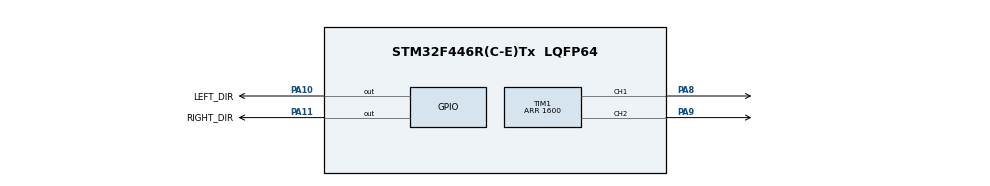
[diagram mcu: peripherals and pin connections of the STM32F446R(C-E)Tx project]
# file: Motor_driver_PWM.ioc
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Mcu.Family=STM32F4
Mcu.Name=STM32F446R(C-E)Tx
Mcu.Package=LQFP64
NVIC.PriorityGroup=NVIC_PRIORITYGROUP_4
PA10.GPIO_Label=LEFT_DIR
PA10.GPIO_Speed=GPIO_SPEED_FREQ_HIGH
PA10.Signal=GPIO_Output
PA11.GPIO_Label=RIGHT_DIR
PA11.GPIO_Speed=GPIO_SPEED_FREQ_HIGH
PA11.Signal=GPIO_Output
PA8.GPIO_Speed=GPIO_SPEED_FREQ_LOW
PA8.Signal=S_TIM1_CH1
PA9.GPIO_Speed=GPIO_SPEED_FREQ_LOW
PA9.Signal=S_TIM1_CH2
PH0-OSC_IN.Mode=HSE-External-Oscillator
PH0-OSC_IN.Signal=RCC_OSC_IN
PH1-OSC_OUT.Mode=HSE-External-Oscillator
PH1-OSC_OUT.Signal=RCC_OSC_OUT
ProjectManager.HeapSize=0x200
ProjectManager.StackSize=0x400
ProjectManager.TargetToolchain=STM32CubeIDE
RCC.AHBCLKDivider=RCC_SYSCLK_DIV2
RCC.AHBFreq_Value=32000000
RCC.APB1Freq_Value=32000000
RCC.APB1TimFreq_Value=32000000
RCC.APB2Freq_Value=32000000
RCC.APB2TimFreq_Value=32000000
RCC.CortexFreq_Value=32000000
RCC.HCLKFreq_Value=32000000
RCC.PLLM=8
RCC.PLLN=64
RCC.SYSCLKFreq_VALUE=64000000
RCC.SYSCLKSource=RCC_SYSCLKSOURCE_PLLCLK
RCC.USBFreq_Value=64000000
RCC.VCOOutputFreq_Value=128000000
SH.S_TIM1_CH1.0=TIM1_CH1,PWM Generation1 CH1
SH.S_TIM1_CH2.0=TIM1_CH2,PWM Generation2 CH2
TIM1.Channel-PWM\ Generation1\ CH1=TIM_CHANNEL_1
TIM1.Channel-PWM\ Generation2\ CH2=TIM_CHANNEL_2
TIM1.OCMode_PWM-PWM\ Generation2\ CH2=TIM_OCMODE_PWM2
TIM1.Period=1600
TIM1.Pulse-PWM\ Generation1\ CH1=800
TIM1.Pulse-PWM\ Generation2\ CH2=800
board=custom

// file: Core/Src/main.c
/* USER CODE BEGIN Header */
/**
  ******************************************************************************
  * @file           : main.c
  * @brief          : Main program body
  ******************************************************************************
  * @attention
  *
  * <h2><center>&copy; Copyright (c) 2020 STMicroelectronics.
  * All rights reserved.</center></h2>
  *
  * This software component is licensed by ST under BSD 3-Clause license,
  * the "License"; You may not use this file except in compliance with the
  * License. You may obtain a copy of the License at:
  *                        opensource.org/licenses/BSD-3-Clause
  *
  ******************************************************************************
  */
/* USER CODE END Header */
#include "main.h"

TIM_HandleTypeDef htim1;

void SystemClock_Config(void);
static void MX_GPIO_Init(void);

/* USER CODE BEGIN PFP */
void move_forward(int pulse);
void turn_left(int pulse);
void turn_right(int pulse);
void reverse(int pulse);
void stop_robot(void);
static void MX_TIM1_Init(void);

/* USER CODE END PFP */

int main(void)
{

  /* MCU Configuration--------------------------------------------------------*/

  /* Reset of all peripherals, Initializes the Flash interface and the Systick. */
  HAL_Init();

  /* Configure the system clock */
  SystemClock_Config();

  /* Initialize all configured peripherals */
  MX_GPIO_Init();
  MX_TIM1_Init();

  /* USER CODE BEGIN 2 */
  HAL_TIM_PWM_Start(&htim1, TIM_CHANNEL_1);
  HAL_TIM_PWM_Start(&htim1, TIM_CHANNEL_2);

  /* USER CODE END 2 */

  /* Infinite loop */
  while (1)
  {

  }
}

void SystemClock_Config(void)
{
  RCC_OscInitTypeDef RCC_OscInitStruct = {0};
  RCC_ClkInitTypeDef RCC_ClkInitStruct = {0};

  /** Configure the main internal regulator output voltage
  */

  __HAL_RCC_PWR_CLK_ENABLE();
  __HAL_PWR_VOLTAGESCALING_CONFIG(PWR_REGULATOR_VOLTAGE_SCALE3);

  /** Initializes the RCC Oscillators according to the specified parameters
  * in the RCC_OscInitTypeDef structure.
  */

  RCC_OscInitStruct.OscillatorType = RCC_OSCILLATORTYPE_HSI;
  RCC_OscInitStruct.HSIState = RCC_HSI_ON;
  RCC_OscInitStruct.HSICalibrationValue = RCC_HSICALIBRATION_DEFAULT;
  RCC_OscInitStruct.PLL.PLLState = RCC_PLL_NONE;

  if (HAL_RCC_OscConfig(&RCC_OscInitStruct) != HAL_OK)
  {
    Error_Handler();
  }

  /** Initializes the CPU, AHB and APB buses clocks
  */
  RCC_ClkInitStruct.ClockType = RCC_CLOCKTYPE_HCLK|RCC_CLOCKTYPE_SYSCLK
                              |RCC_CLOCKTYPE_PCLK1|RCC_CLOCKTYPE_PCLK2;
  RCC_ClkInitStruct.SYSCLKSource = RCC_SYSCLKSOURCE_HSI;
  RCC_ClkInitStruct.AHBCLKDivider = RCC_SYSCLK_DIV1;
  RCC_ClkInitStruct.APB1CLKDivider = RCC_HCLK_DIV1;
  RCC_ClkInitStruct.APB2CLKDivider = RCC_HCLK_DIV1;

  if (HAL_RCC_ClockConfig(&RCC_ClkInitStruct, FLASH_LATENCY_0) != HAL_OK)
  {
    Error_Handler();
  }
}

static void MX_TIM1_Init(void)
{

  TIM_MasterConfigTypeDef sMasterConfig = {0};
  TIM_OC_InitTypeDef sConfigOC = {0};
  TIM_BreakDeadTimeConfigTypeDef sBreakDeadTimeConfig = {0};

  htim1.Instance = TIM1;
  htim1.Init.Prescaler = 0;
  htim1.Init.CounterMode = TIM_COUNTERMODE_UP;

  // 16 MHz / 800 = 20kHz frequency of PWM
  htim1.Init.Period = 800;
  htim1.Init.ClockDivision = TIM_CLOCKDIVISION_DIV1;
  htim1.Init.RepetitionCounter = 0;
  htim1.Init.AutoReloadPreload = TIM_AUTORELOAD_PRELOAD_DISABLE;

  if (HAL_TIM_PWM_Init(&htim1) != HAL_OK)
  {
    Error_Handler();
  }

  sMasterConfig.MasterOutputTrigger = TIM_TRGO_RESET;
  sMasterConfig.MasterSlaveMode = TIM_MASTERSLAVEMODE_DISABLE;

  if (HAL_TIMEx_MasterConfigSynchronization(&htim1, &sMasterConfig) != HAL_OK)
  {
    Error_Handler();
  }

  sConfigOC.OCMode = TIM_OCMODE_PWM1;

  // (pulse/period)*100 = duty cycle
  sConfigOC.Pulse = 0;
  sConfigOC.OCPolarity = TIM_OCPOLARITY_HIGH;
  sConfigOC.OCNPolarity = TIM_OCNPOLARITY_HIGH;
  sConfigOC.OCFastMode = TIM_OCFAST_DISABLE;
  sConfigOC.OCIdleState = TIM_OCIDLESTATE_RESET;
  sConfigOC.OCNIdleState = TIM_OCNIDLESTATE_RESET;

  if (HAL_TIM_PWM_ConfigChannel(&htim1, &sConfigOC, TIM_CHANNEL_1) != HAL_OK)
  {
    Error_Handler();
  }

  if (HAL_TIM_PWM_ConfigChannel(&htim1, &sConfigOC, TIM_CHANNEL_2) != HAL_OK)
  {
    Error_Handler();
  }

  sBreakDeadTimeConfig.OffStateRunMode = TIM_OSSR_DISABLE;
  sBreakDeadTimeConfig.OffStateIDLEMode = TIM_OSSI_DISABLE;
  sBreakDeadTimeConfig.LockLevel = TIM_LOCKLEVEL_OFF;
  sBreakDeadTimeConfig.DeadTime = 0;
  sBreakDeadTimeConfig.BreakState = TIM_BREAK_DISABLE;
  sBreakDeadTimeConfig.BreakPolarity = TIM_BREAKPOLARITY_HIGH;
  sBreakDeadTimeConfig.AutomaticOutput = TIM_AUTOMATICOUTPUT_DISABLE;

  if (HAL_TIMEx_ConfigBreakDeadTime(&htim1, &sBreakDeadTimeConfig) != HAL_OK)
  {
    Error_Handler();
  }
  HAL_TIM_MspPostInit(&htim1);

}

static void MX_GPIO_Init(void)
{
  GPIO_InitTypeDef GPIO_InitStruct = {0};

  /* GPIO Ports Clock Enable */
  __HAL_RCC_GPIOH_CLK_ENABLE();
  __HAL_RCC_GPIOA_CLK_ENABLE();

  /*Configure GPIO pin Output Level */
  HAL_GPIO_WritePin(GPIOA, LEFT_DIR_Pin|RIGHT_DIR_Pin, GPIO_PIN_RESET);

  /*Configure GPIO pins : LEFT_DIR_Pin RIGHT_DIR_Pin */
  GPIO_InitStruct.Pin = LEFT_DIR_Pin|RIGHT_DIR_Pin;
  GPIO_InitStruct.Mode = GPIO_MODE_OUTPUT_PP;
  GPIO_InitStruct.Pull = GPIO_NOPULL;
  GPIO_InitStruct.Speed = GPIO_SPEED_FREQ_HIGH;
  HAL_GPIO_Init(GPIOA, &GPIO_InitStruct);

}

/* USER CODE BEGIN 4 */
void stop_robot(void)
{
	//Clears PA11
	HAL_GPIO_WritePin(RIGHT_DIR_GPIO_Port, RIGHT_DIR_Pin, GPIO_PIN_RESET);

	//Clears PA10
	HAL_GPIO_WritePin(LEFT_DIR_GPIO_Port, LEFT_DIR_Pin, GPIO_PIN_RESET);

	//__HAL_TIM_SET_COMPARE(Handle, channel, pulse width)
	//Adjust the pulse width between 0 to 800 to adjust duty cycle.
	__HAL_TIM_SET_COMPARE(&htim1, TIM_CHANNEL_1, 0);
	__HAL_TIM_SET_COMPARE(&htim1, TIM_CHANNEL_2, 0);
}
void move_forward(int pulse)
{
	//__HAL_TIM_SET_COMPARE(Handle, channel, pulse width)
	//Adjust the pulse width between 0 to 800 to adjust duty cycle.

	__HAL_TIM_SET_COMPARE(&htim1, TIM_CHANNEL_1, pulse);
	__HAL_TIM_SET_COMPARE(&htim1, TIM_CHANNEL_2, pulse);
}

void turn_left(int pulse)
{
	//Sets PA10
	HAL_GPIO_WritePin(LEFT_DIR_GPIO_Port, LEFT_DIR_Pin, GPIO_PIN_SET);

	//Clears PA11
	HAL_GPIO_WritePin(RIGHT_DIR_GPIO_Port, RIGHT_DIR_Pin, GPIO_PIN_RESET);

	//__HAL_TIM_SET_COMPARE(Handle, channel, pulse width)
	//Adjust the pulse width between 0 to 800 to adjust duty cycle.

	__HAL_TIM_SET_COMPARE(&htim1, TIM_CHANNEL_1, pulse);
	__HAL_TIM_SET_COMPARE(&htim1, TIM_CHANNEL_2, pulse);
}

void turn_right(int pulse)
{
	//Sets PA11
	HAL_GPIO_WritePin(RIGHT_DIR_GPIO_Port, RIGHT_DIR_Pin, GPIO_PIN_SET);

	//Clears PA10
	HAL_GPIO_WritePin(LEFT_DIR_GPIO_Port, LEFT_DIR_Pin, GPIO_PIN_RESET);

	//__HAL_TIM_SET_COMPARE(Handle, channel, pulse width)
	//Adjust the pulse width between 0 to 800 to adjust duty cycle.

	__HAL_TIM_SET_COMPARE(&htim1, TIM_CHANNEL_1, pulse);
	__HAL_TIM_SET_COMPARE(&htim1, TIM_CHANNEL_2, pulse);

}

void reverse(int pulse)
{
	//Sets PA11
	HAL_GPIO_WritePin(RIGHT_DIR_GPIO_Port, RIGHT_DIR_Pin, GPIO_PIN_SET);

	//Sets PA10
	HAL_GPIO_WritePin(LEFT_DIR_GPIO_Port, LEFT_DIR_Pin, GPIO_PIN_SET);

	//__HAL_TIM_SET_COMPARE(Handle, channel, pulse width)
	//Adjust the pulse width between 0 to 800 to adjust duty cycle.
	__HAL_TIM_SET_COMPARE(&htim1, TIM_CHANNEL_1, pulse);
	__HAL_TIM_SET_COMPARE(&htim1, TIM_CHANNEL_2, pulse);
}
/* USER CODE END 4 */

void Error_Handler(void)
{
}

/************************ (C) COPYRIGHT STMicroelectronics *****END OF FILE****/
